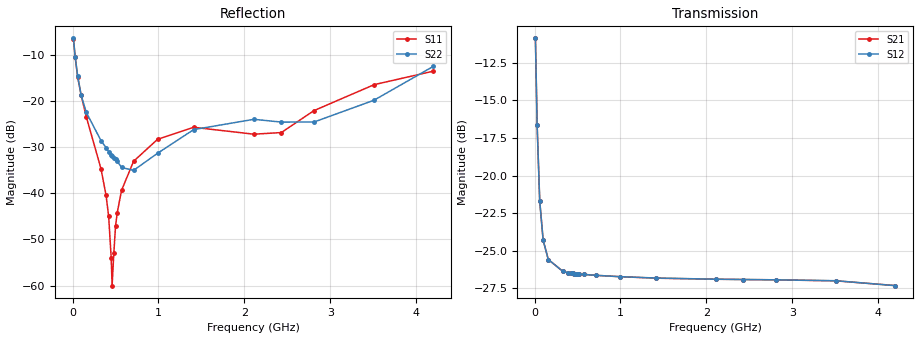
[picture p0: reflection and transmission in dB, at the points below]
! Integrated Device Technology
! Corporate Headquarters
! 6024 Silver Creek Valley Road
! San Jose, CA 95138  USA
! Phone:  1-408-284-8200
! Toll Free:  1-800-223-1366
! Webpage:  http://www.idt.com/
! Timing and RF Division
! 515 Groton Road, Suite 102
! Westford, MA 01886-6024
! Device:  F1950
! Description: 7-bit 0.25 dB Digital Step Attenuator
! Frequency:  150.0 -  4000.00 MHz
! Package:  4x4 mm Thin QFN Plastic Package: 24 pin
! Ports:  2 RF, 12 DC
!  Pin  1  = D0
!  Pin  2  = VDD
!  Pin  3  = Vmode
!  Pin  4  = GND
!  Pin  5  = RF1  =  Port 1
!  Pin  6  = GND
!  Pin  7  = GND
!  Pin  8  = GND
!  Pin  9  = GND
!  Pin 10  = GND
!  Pin 11  = GND
!  Pin 12  = GND
!  Pin 13  = GND
!  Pin 14  = RF2  =  Port 2
!  Pin 15  = GND
!  Pin 16  = LE
!  Pin 17  = CLK
!  Pin 18  = DATE
!  Pin 19  = D6
!  Pin 20  = D5
!  Pin 21  = D4
!  Pin 22  = D3
!  Pin 23  = D2
!  Pin 24  = D1
! State:  103
! Atten State:  25.75 dB
! Voltage:  +5.00 Volts
! Current:  Not Measured mA
! Data:  The device was measured on a the F195X evaluation board which has
!  individual transmission lines to the RF pins.  Data was collected
!  using a calibrated network analyzer.  The evaluation board was
!  de-embedded using a TRL calibration technique.
!  The reference plane is the edge of the package pin.
! Misc:  Board 2019
!  Action Tracker AT0250
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# GHz S dB R 50
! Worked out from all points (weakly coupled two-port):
!   420 points, 10 MHz to 4.2 GHz, reference 50 ohm
!   highest |S21| = -10.88 dB at 10 MHz (marker M1); lowest = -27.3 dB at 4.2 GHz (marker M2)
!   lowest |S11| = -60.0 dB at 460 MHz (marker M3), VSWR 1.00, Z = 49.9 - j0.0807 ohm
!   |S11| at or under -10 dB: 27.41 MHz to end of sweep
!   |S22| runs from -35.3 to -6.4 dB; largest |S21 - S12| = 9.6e-05
!   S11 on the Smith chart (normalised r, x): 10 MHz: 2.05, -1.12; 30 MHz: 1.29, -0.65; 60 MHz: 1.11, -0.37; 390 MHz: 1.01, -0.02; 4.2 GHz: 0.69, +0.17
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0.01  -6.51 -26.7  -10.88 -34.3  -10.88 -34.3  -6.45 -27.5
0.03  -10.49 -50.2  -16.66 -53.4  -16.66 -53.4  -10.41 -51.5
0.06  -14.92 -63.3  -21.68 -49.3  -21.68 -49.3  -14.69 -64.8
0.1  -18.79 -70.0  -24.30 -37.8  -24.30 -37.8  -18.76 -70.3
0.16  -23.46 -71.6  -25.58 -27.2  -25.58 -27.2  -22.49 -75.1
0.33  -34.64 -69.1  -26.37 -16.9  -26.37 -16.9  -28.57 -83.1
0.39  -40.47 -67.5  -26.45 -15.6  -26.45 -15.6  -30.12 -85.3
0.42  -44.99 -73.0  -26.48 -15.2  -26.48 -15.2  -30.98 -87.3
0.45  -54.11 -90.4  -26.50 -14.8  -26.50 -14.8  -31.76 -91.7
0.46  -60.01 -126.0  -26.51 -14.7  -26.51 -14.7  -31.95 -93.3
0.48  -53.03 144.4  -26.52 -14.6  -26.52 -14.6  -32.27 -96.1
0.5  -47.15 135.9  -26.54 -14.4  -26.54 -14.4  -32.61 -97.9
0.52  -44.19 135.2  -26.55 -14.3  -26.55 -14.3  -33.08 -99.4
0.57  -39.37 132.1  -26.57 -14.2  -26.57 -14.2  -34.40 -108.8
0.71  -33.07 136.4  -26.63 -14.2  -26.63 -14.2  -35.04 -137.0
0.99  -28.30 146.5  -26.72 -15.4  -26.72 -15.4  -31.32 -179.5
1.41  -25.71 162.5  -26.82 -18.3  -26.81 -18.3  -26.21 160.5
2.11  -27.20 157.1  -26.89 -24.3  -26.89 -24.3  -23.98 142.0
2.43  -26.85 124.9  -26.91 -26.9  -26.91 -26.9  -24.58 131.1
2.81  -22.10 104.4  -26.93 -30.7  -26.93 -30.7  -24.57 115.6
3.51  -16.48 116.8  -27.00 -37.2  -26.99 -37.2  -19.84 113.1
4.2  -13.55 145.4  -27.31 -41.4  -27.32 -41.5  -12.51 127.1
